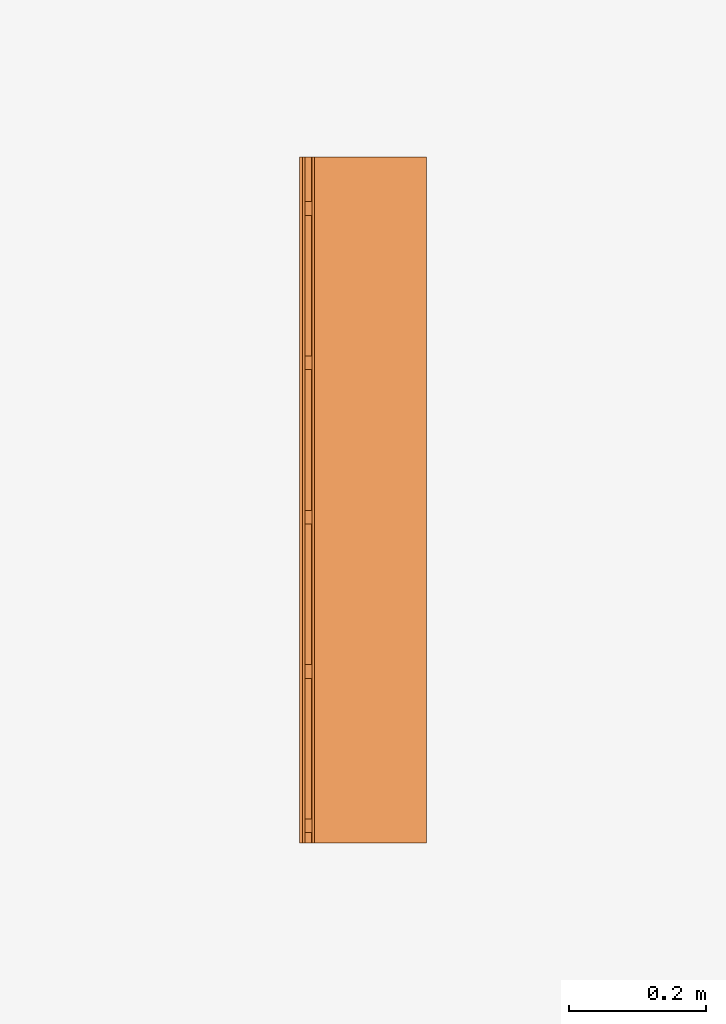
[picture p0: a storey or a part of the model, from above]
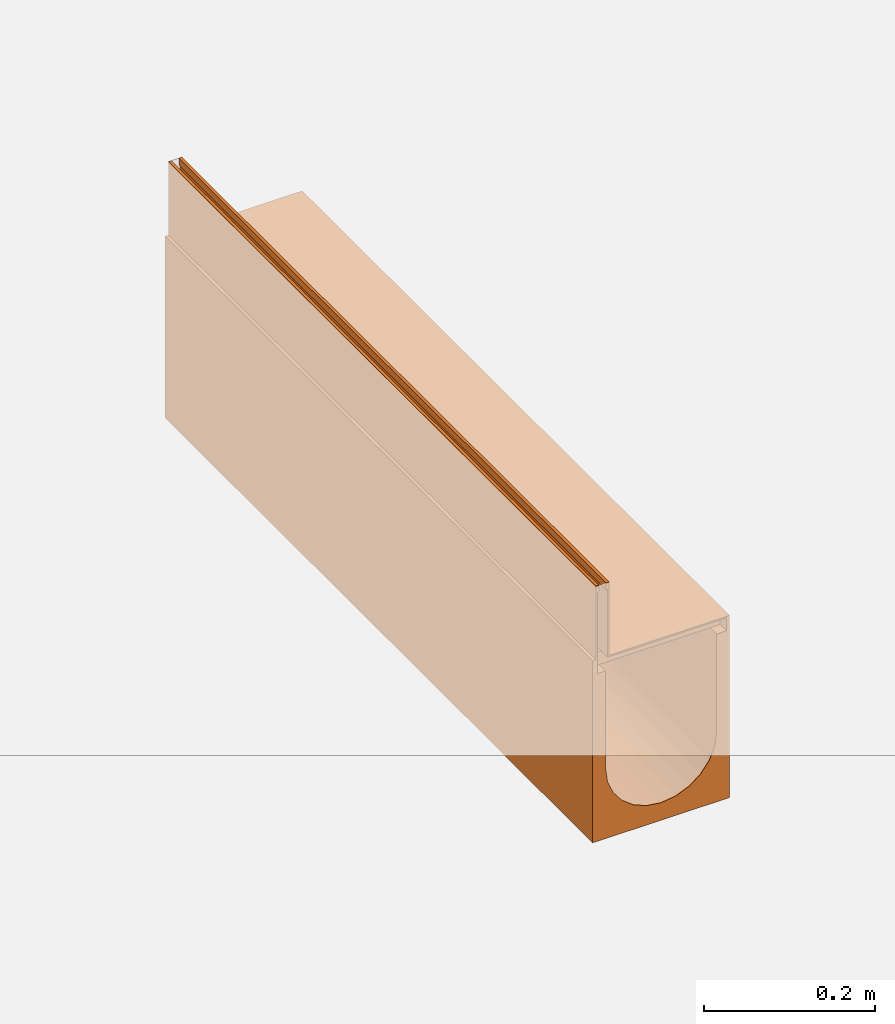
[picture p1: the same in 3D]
Properties of the parts of a building model (IFC2X3)

# File
Description: ViewDefinition [CoordinationView]
File name: 23151 - No 10.0 Constant Depth Channel - 1000mm LG - Invert Depth 235mm.ifc
Time: 2013-10-30T12:20:54
Written by: Autodesk Revit 2013
Made in: 20120221_2030(x64)

# IfcProject, Project Number
LongName: Project Name; Phase: Project Status

# IfcSite, Default
RefLatitude: 42, 21, 30, 344238; RefLongitude: -71, -3, -35, -194702; RefElevation: 0 mm

# IfcBuilding
Pset_BuildingCommon - NumberOfStoreys: 1
Other - Project Address: ## Street City, State Zip; Project Name: Project Name; Project Status: Project Status; Project Number: Project Number; Project Issue Date: Issue Date; Client Name: Owner

# IfcBuildingStorey, Level 1
LongName: Level 1; Elevation: 0 mm
Constraints - Elevation Base: 0; Elevation: 0 mm
Graphics - Line Pattern: Center; Symbol at End 2 Default: yes; Symbol at End 1 Default: no; Color: 0; Symbol: M_Level Head - Circle: M_Level Head - Circle; Line Weight: 1
Identity Data - Building Story: yes; Name: Level 1; Structural: no
Dimensions - Computation Height: 0 mm

# IfcBuildingElementProxy: 23151 - No 10.0 Constant Depth Channel - 1000mm LG - Invert Depth 235mm, Civil-Drainage-Channel-ACO-MultiDrain-M150D-Brickslot-Channel-System:23151 - No 10.0 Constant Depth Channel - 1000mm LG - Invert Depth 235mm:23151 - No 10.0 Constant Depth Channel - 1000mm LG - Invert Depth 235mm:196059
In: Level 1
Material: Steel, Galvanized, Vienite® Synthetic Resin Concrete
Dimensions - Brickslot Access Unit Void Bottom Depth: -6105 mm; Brickslot Void Length: -1000 mm; FloorCut_Length: -1000 mm; Custom_Void_Length: 0 mm; Brickslot Access Unit Void Depth: -6000 mm; Brickslot Grating Void Depth: 0 mm; EndCap Position: 1000 mm; Volume: 15462793 mm3; Length: 1000 mm; FloorCut_Depth: 260 mm; Depth: 260 mm; Floor cut gap depth for access unit: 105 mm; End Cap Thickess: 3 mm; EndCap_Height: -260 mm; FloorCut_Width: 185 mm; Length Drain: -1000 mm; FloorCut_HorPosition: 92.5 mm; Floor Cut Gap: 105 mm; InvDepth: 160 mm
Construction - 23176_Load Class C250 & D400_Brickslot Grating_Galvanized Steel_500mm Long: no; 23159_Universal Endcap (Female End): no; 23159_Universal Endcap (Male End): no; 23177_Load Class C250 & D400_Brickslot_Access Unit_Galvanized Steel_500mm Long: no; 23175_Load Class C250 & D400_Brickslot Grating_Galvanized Steel_1000mm Long: yes; 23156_Shallow Depth Channel: no; 23157_Shallow Depth Channel with seal: no; Constant Depth Channel_1000: yes; Constant Depth Channel_500: no; Sump Unit: no
Phasing - Phase Created: New Construction
Constraints - Level: Level: Level 1; Moves With Nearby Elements: no
Pset_BuildingElementProxyCommon - Reference: 23151 - No 10.0 Constant Depth Channel - 1000mm LG - Invert Depth 235mm
Data - Pre-formed Outlet Ø: N/A; Concrete Surround Volume - Load Class B 125 - C 250 - Concrete Pavement: 0.16m³/m; Hydraulic Performance: http://www.aco.co.uk/download.php?id=173; ACO Hydraulic Design Software: http://www.acodesign.co.uk; Product Dimensions: 1000mm x 185mm x 260mm (LxWxH); Invert Depth: 235mm; Concrete Surround Volume - Load Class D 400 - Concrete Pavement: 0.23m³/m; Product Standard: BS EN 1433:2002, CE marked; Product Weight: 25.0 Kg; Load Class: A 15 - D 400; Concrete Surround Volume - Load Class A 15 - Concrete Pavement: 0.10m³/m; Installation - Concrete Grade: Refer to brochure; Channel C.S.A: 0.026m²
General - SerialNumber: 0; TagNumber: 0
Other - CreatedBy: www.aco.co.uk; Revision: 1
Green Building Properties - Channel Recycled Material Content: 20% minimum; Edge Rail Recycled Material Content: Between 40% - 90%; Edge Rail Recyclable: Fully recyclable; Channel Recyclable: Fully recyclable
Model Properties - Brickslot Access Unit Product code 23177: Load Class C250/D400 - Brickslot Access Unit Galvanised steel - 500mm long x 105mm high - 10mm Slot -Intake area 10000mm²/m - 7.0kg; Brickslot Grating Product code 23175: Load Class C250/D400 - Brickslot Galvanized Steel - 1000mm long x 105mm high - 10mm Slot - Intake area 10000mm²/m - 7.6kg; End Cap Product code 23159: No. 306 Universal End Cap - 185mm wide x 310mm long - Spigot Ø110mm x 50mm long - Silver - Co-Polymer Polypropylene - 0.3kg; Brickslot Grating Product code 23176: Load Class C250/D400 -Brickslot Galvanized Steel - 500mm long x 105mm high - 10mm Slot - Intake area 10000mm²/m - 3.8kg
Identity Data - Cost: 0; e-mail Sales: customersupport@aco.co.uk; OmniClass Title: Rainwater Removal; Fax: +44 (0)1462 815895; Watermark 1: This file is the property of ACO Technologies PLC; Installation guidelines: http://www.aco.co.uk/download.php?id=173; Model: ACO MultiDrain MD Brickslot - M150D; OmniClass Number: 23.70.50.24; URL: www.aco.co.uk; Address: ACO Business Park, Hitchin Road, Shefford, Bedfordshire, United Kingdom SG17 5TE; Assembly Code: D2040; Price: POA - contact ACO; Product Page URL: http://www.aco.co.uk/product_detail.php?id=58; Product brochure: http://www.aco.co.uk/download.php?id=173; Model Description: Channel drainage system; e-mail Technical: technical@aco.co.uk; Watermark 2: This file is water marked and users are prohibited to reproduce, adapt, distribute this information; Watermarked By: www.aco.co.uk; Manufacturer: ACO Technologies plc - ACO Water Management Division; Product Code: 23151; Type Comments: ACO MultiDrain M150D 10.0 Constant Depth Channel 1000mm Long; Telephone: +44 (0)1462 816666; Assembly Description: Rain Water Drainage; Maintenance guidelines: http://www.aco.co.uk/download.php?id=173; Watermarked With: BIM Manager Premium Suite
Materials and Finishes - Edge Rail Colour: Silver; Edge Rail Finish: Pre-galvanised; Channel Material: Vienite® Synthetic Resin Concrete; Edge Rail Material: Steel; Channel Colour: Brown

# IfcOpeningElement: Recess (2)
In: Level 1
Constraints - Related to Mass: no; Level: Level: Level 1; Room Bounding: yes; Height Offset From Level: 0 mm
Dimensions - Thickness: 400 mm; Area: 25000000 mm2; Volume: 9950010000 mm3; Perimeter: 20000 mm
Structural - Structural: no; Enable Analytical Model: no
Phasing - Phase Created: New Construction
Graphics - Coarse Scale Fill Color: 0
Materials and Finishes - Structural Material: Earth
Construction - Default Thickness: 400 mm; Function: 0
Analytical Properties - Absorptance: 0.1; Thermal mass: 543920; Thermal Resistance (R): 0.477897; Heat Transfer Coefficient (U): 2.0925; Roughness: 1

# IfcSlab: Floor:Generic Floor - 400mm, Floor:Generic Floor - 400mm:193825
In: Level 1
PredefinedType: FLOOR; Material: Earth 400 mm
Constraints - Related to Mass: no; Level: Level: Level 1; Room Bounding: yes; Height Offset From Level: 0 mm
Dimensions - Thickness: 400 mm; Area: 25000000 mm2; Volume: 9950010000 mm3; Perimeter: 20000 mm
Structural - Structural: no; Enable Analytical Model: no
Phasing - Phase Created: New Construction
Pset_SlabCommon - Reference: Generic Floor - 400mm; IsExternal: no; LoadBearing: yes
Graphics - Coarse Scale Fill Color: 0
Materials and Finishes - Structural Material: Earth
Construction - Default Thickness: 400 mm; Function: 0
Analytical Properties - Absorptance: 0.1; Thermal mass: 543920; Thermal Resistance (R): 0.477897; Heat Transfer Coefficient (U): 2.0925; Roughness: 1
